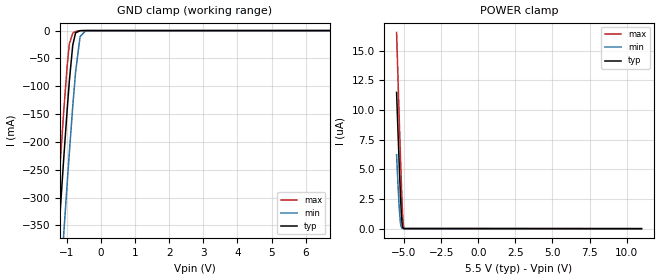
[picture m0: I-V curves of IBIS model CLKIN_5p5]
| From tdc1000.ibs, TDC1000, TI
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|   Model
[Model]   CLKIN_5p5
Model_type   Input
Vinl = 1.65
Vinh = 3.85
|   typ   min   max
C_comp   0.373pF   0.351pF   0.406pF
[Voltage Range]   5.5   5.499   5.501
[Temperature Range]   27   125   -40
[Power Clamp Reference]   5.5   5.499   5.501
[GND Clamp Reference]   0   0   0
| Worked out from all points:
|   GND clamp passes 1 mA (typ) near -0.69 V on its own axis
[GND Clamp]
|   Voltage   I(typ)   I(min)   I(max)
-5.5V     -4.473A    -4.568A    -4.415A
-1.359V   -474.1mA   -611.4mA   -387.5mA
-1.309V   -427.3mA   -564.7mA   -340.7mA
-1.243V   -365.5mA   -502.7mA   -278.9mA
-1.095V   -229.5mA   -365.4mA   -144.7mA
-995.5mV  -143.3mA   -276.2mA   -64.2mA
-929.5mV  -90mA      -218.4mA   -24mA
-830.5mV  -26.18mA   -136mA     -4.536mA
-748mV    -4.143mA   -74.65mA   -1.443mA
-616mV    -185.8uA   -10.91mA   -75.06uA
-451mV    -2.226uA   -154.6uA   -400.4nA
11V       0A         0A         0A
[POWER Clamp]
|   Voltage   I(typ)   I(min)   I(max)
-5.5V     11.49uA    6.236uA    16.55uA
-5.401V   8.03uA     3.58uA     12.5uA
-5.319V   5.271uA    1.698uA    9.186uA
-5.253V   3.219uA    638.5nA    6.611uA
-5.22V    2.288uA    328.3nA    5.362uA
-5.186V   1.462uA    154.7nA    4.154uA
-5.137V   539.9nA    51.19nA    2.462uA
-5.104V   207.3nA    28.86nA    1.476uA
-5.071V   63.47nA    19.87nA    696.4nA
-5.038V   14.99nA    16.16nA    227.4nA
-4.989V   282.6pA    14.02nA    20.03nA
11V       0A         0A         0A
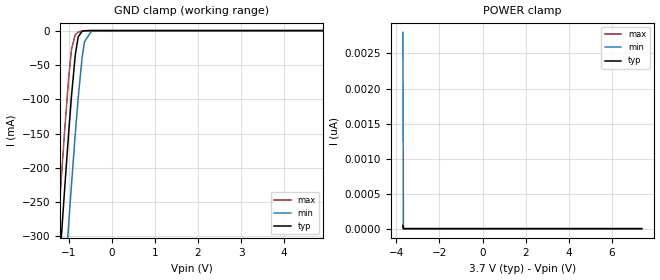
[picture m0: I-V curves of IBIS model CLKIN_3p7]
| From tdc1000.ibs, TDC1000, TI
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|   Model
[Model]   CLKIN_3p7
Model_type   Input
Vinl = 1.19
Vinh = 2.59
|   typ   min   max
C_comp   0.373pF   0.351pF   0.406pF
[Voltage Range]   3.7   3.699   3.701
[Temperature Range]   27   125   -40
[Power Clamp Reference]   3.7   3.699   3.701
[GND Clamp Reference]   0   0   0
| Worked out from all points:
|   GND clamp passes 1 mA (typ) near -0.69 V on its own axis
[GND Clamp]
|   Voltage   I(typ)   I(min)   I(max)
-3.7V     -2.734A    -2.848A    -2.663A
-1.347V   -463mA     -600.3mA   -376.4mA
-1.236V   -358.8mA   -496mA     -272.3mA
-1.091V   -226.8mA   -362.7mA   -142.1mA
-1.003V   -149.3mA   -282.6mA   -69.51mA
-936.1mV  -95.08mA   -224.1mA   -27.08mA
-847.3mV  -34.72mA   -149.5mA   -5.651mA
-780.7mV  -9.157mA   -97.83mA   -2.372mA
-691.9mV  -1.101mA   -40.32mA   -491.9uA
-636.4mV  -303uA     -16.52mA   -129.2uA
-469.9mV  -3.875uA   -258.6uA   -788.3nA
7.4V      0A         0A         0A
[POWER Clamp]
|   Voltage   I(typ)   I(min)   I(max)
-3.7V     48.15pA    2.801nA    37.18pA
-3.678V   0A         0A         0A
-3.667V   0A         0A         0A
7.4V      0A         0A         0A
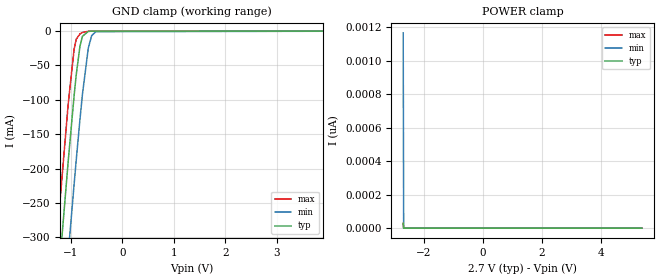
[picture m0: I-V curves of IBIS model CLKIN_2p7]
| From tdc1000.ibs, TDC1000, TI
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|   Model
[Model]   CLKIN_2p7
Model_type   Input
Vinl = 0.81
Vinh = 1.89
|   typ   min   max
C_comp   0.373pF   0.351pF   0.406pF
[Voltage Range]   2.7   2.699   2.701
[Temperature Range]   27   125   -40
[Power Clamp Reference]   2.7   2.699   2.701
[GND Clamp Reference]   0   0   0
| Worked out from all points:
|   GND clamp passes 1 mA (typ) near -0.68 V on its own axis
[GND Clamp]
|   Voltage   I(typ)   I(min)   I(max)
-2.7V     -1.768A    -1.892A    -1.689A
-1.436V   -548.1mA   -685.3mA   -461.7mA
-1.218V   -342mA     -479.1mA   -255.5mA
-1.048V   -188mA     -322.8mA   -104.9mA
-934.2mV  -93.62mA   -222.5mA   -26.16mA
-893.7mV  -63.79mA   -187.9mA   -11.99mA
-820.8mV  -21.87mA   -128.4mA   -4.009mA
-772.2mV  -7.471mA   -91.63mA   -2.099mA
-658.8mV  -512.6uA   -24.66mA   -227.7uA
-594mV    -108uA     -6.655mA   -40.59uA
-513mV    -13.05uA   -831.2uA   -3.392uA
5.4V      0A         0A         0A
[POWER Clamp]
|   Voltage   I(typ)   I(min)   I(max)
-2.7V     29.93pA    1.165nA    27.04pA
-2.684V   0A         0A         0A
-2.676V   0A         0A         0A
5.4V      0A         0A         0A
